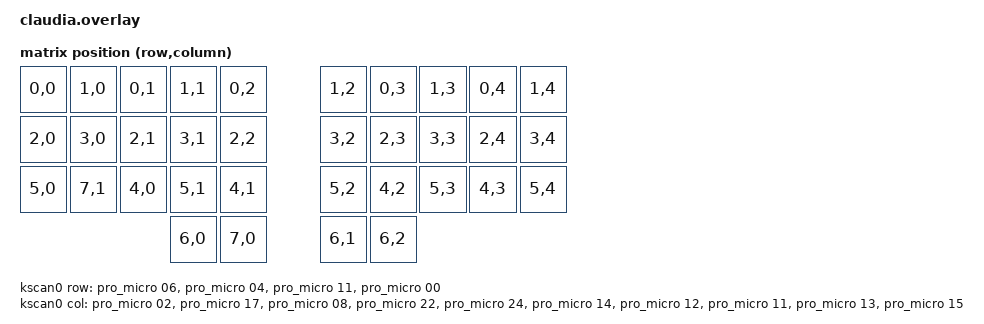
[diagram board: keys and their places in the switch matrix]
/*
 * Copyright (c) 2020 The ZMK Contributors
 *
 * SPDX-License-Identifier: MIT
 */

#include <dt-bindings/zmk/matrix_transform.h>

/ {
	chosen {
		zmk,kscan = &kscan0;
	};
 
	kscan0: kscan_0{
		compatible = "zmk,kscan-gpio-matrix";
        diode-direction = "row2col";
	wakeup-source;

	row-gpios 	
		= <&pro_micro 06 (GPIO_ACTIVE_HIGH | GPIO_PULL_DOWN)>
		, <&pro_micro 04 (GPIO_ACTIVE_HIGH | GPIO_PULL_DOWN)>
		, <&pro_micro 11 (GPIO_ACTIVE_HIGH | GPIO_PULL_DOWN)>
		, <&pro_micro 00 (GPIO_ACTIVE_HIGH | GPIO_PULL_DOWN)>
		;
			
	col-gpios	
		= <&pro_micro 02  GPIO_ACTIVE_HIGH>
		, <&pro_micro 17  GPIO_ACTIVE_HIGH>
		, <&pro_micro 08  GPIO_ACTIVE_HIGH>
		, <&pro_micro 22  GPIO_ACTIVE_HIGH>
		, <&pro_micro 24  GPIO_ACTIVE_HIGH>
                , <&pro_micro 14  GPIO_ACTIVE_HIGH>
               	, <&pro_micro 12  GPIO_ACTIVE_HIGH>
                , <&pro_micro 11  GPIO_ACTIVE_HIGH>
                , <&pro_micro 13  GPIO_ACTIVE_HIGH>
		, <&pro_micro 15  GPIO_ACTIVE_HIGH>
		;

/ {
 	/* define keyscna node with label 'kscan0'...*/

	default_transform: keymap_transform_0 {
		compatible = "zmk,matrix-transform";
		rows = <4>;
        	columns = <10>;

        	map = <
        RC(0,0) RC(1,0) RC(0,1) RC(1,1) RC(0,2) RC(1,2) RC(0,3) RC(1,3) RC(0,4) RC(1,4)
	RC(2,0) RC(3,0) RC(2,1) RC(3,1) RC(2,2) RC(3,2) RC(2,3) RC(3,3) RC(2,4) RC(3,4)
	RC(5,0) RC(7,1) RC(4,0) RC(5,1) RC(4,1) RC(5,2) RC(4,2) RC(5,3) RC(4,3) RC(5,4)
		                RC(6,0) RC(7,0) RC(6,1) RC(6,2)
		>;
	};
	
};
